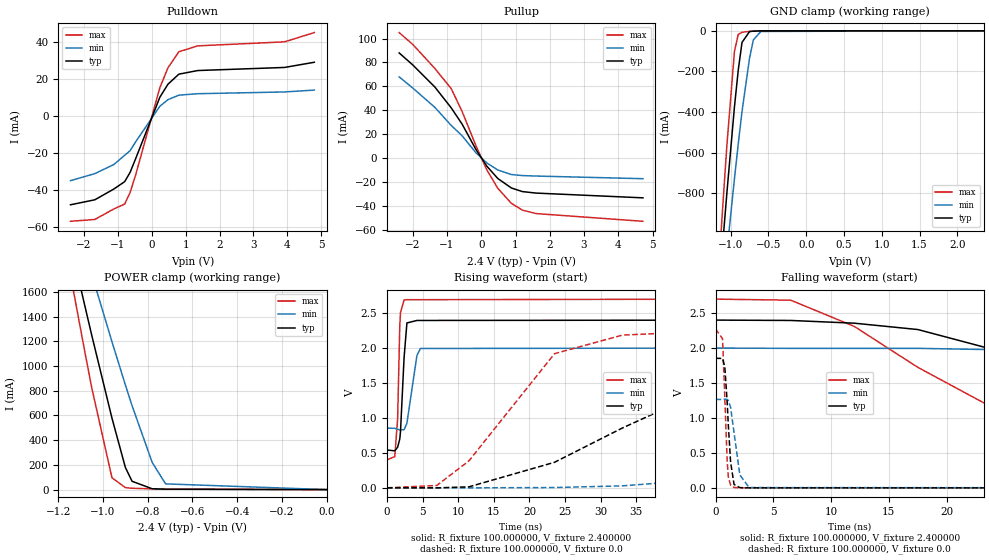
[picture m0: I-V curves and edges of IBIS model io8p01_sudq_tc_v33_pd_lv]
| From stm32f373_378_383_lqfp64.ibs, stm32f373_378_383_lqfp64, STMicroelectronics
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|   Model io8p01_sudq_tc_v33_pd_lv
[Model]  io8p01_sudq_tc_v33_pd_lv
Model_type I/O
Polarity   Non-Inverting
Enable   Active-Low
Vinl =   0.720000V
Vinh =   1.680000V
Vmeas =  1.200000V
Cref =   50.000000pF
Rref =   100.000000M
Vref =   0.0V
C_comp   1.373400pF   1.288200pF   1.481900pF
[Temperature Range]   25.000000   0.125000k   -40.000000
[Pullup Reference]   2.400000V   2.000000V   2.700000V
[Pulldown Reference]   0.0V   0.0V   0.0V
[POWER Clamp Reference]   2.400000V   2.000000V   2.700000V
[GND Clamp Reference]   0.0V   0.0V   0.0V
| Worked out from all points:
|   slope of the pulldown table from 0 to 0.36 V, typ, clamps not added: 25.7 ohm
|   slope of the pullup table from 0 to 0.36 V, typ, clamps not added: 26.8 ohm
|   GND clamp passes 1 mA (typ) near -0.67 V on its own axis
|   POWER clamp passes 1 mA (typ) near -0.60 V on its own axis
|   rising waveform, R_fixture 100.000000, V_fixture 2.400000: 20-80 % time 483ps typ, 801ps min, 337ps max; typ from 0.541 V to 2.4 V
|   rising waveform, R_fixture 100.000000, V_fixture 0.0: 20-80 % time 22.2ns typ, 64.5ns min, 10.4ns max; typ from 0 V to 1.85 V
|   falling waveform, R_fixture 100.000000, V_fixture 2.400000: 20-80 % time 28.7ns typ, 67.7ns min, 14.6ns max; typ from 2.4 V to 0.541 V
|   falling waveform, R_fixture 100.000000, V_fixture 0.0: 20-80 % time 389ps typ, 566ps min, 289ps max; typ from 1.85 V to 0 V
[Pulldown]
|Voltage   I(typ)   I(min)   I(max)
-2.4V     -47.8mA    -34.8mA    -56.7mA
-1.68V    -45.1mA    -31mA      -55.7mA
-1.12V    -39.3mA    -26.1mA    -50.03mA
-800mV    -35.33mA   -21.13mA   -47.42mA
-640mV    -30.33mA   -18.65mA   -41.16mA
-480mV    -23.12mA   -14mA      -31.94mA
240mV     10.22mA    5.339mA    15.38mA
480mV     17.22mA    8.864mA    26.1mA
800mV     22.59mA    11.27mA    34.68mA
1.36V     24.54mA    12.05mA    37.84mA
3.92V     26.2mA     13mA       40mA
4.8V      29mA       14mA       45mA
[Pullup]
|Voltage   I(typ)   I(min)   I(max)
-2.4V     88mA       68mA       105mA
-2V       77.9mA     58.6mA     95mA
-1.36V    59.6mA     42.6mA     75.1mA
-880mV    42.13mA    27.44mA    58.22mA
-560mV    28.45mA    18.75mA    39mA
-160mV    7.44mA     4.66mA     10.64mA
160mV     -6.607mA   -3.947mA   -9.704mA
480mV     -16.91mA   -9.806mA   -25.1mA
880mV     -24.89mA   -13.63mA   -37.75mA
1.2V      -27.87mA   -14.5mA    -43.37mA
1.6V      -29.13mA   -14.89mA   -46.24mA
4.72V     -33.1mA    -17.1mA    -52.7mA
[GND_clamp]
|Voltage   I(typ)   I(min)   I(max)
-2.4V     -7.358A    -6.372A    -8.78A
-1.2V     -1.489A    -1.65A     -1.416A
-1.15V    -1.254A    -1.461A    -1.124A
-1.1V     -1.024A    -1.273A    -838.2mA
-1.05V    -797.6mA   -1.088A    -563.2mA
-950mV    -374.6mA   -728.7mA   -100.8mA
-900mV    -194.3mA   -558mA     -18.03mA
-850mV    -56.96mA   -397.5mA   -7.097mA
-750mV    -3.597mA   -133.8mA   -2.788mA
-700mV    -1.53mA    -44.71mA   -1.533mA
-600mV    -249.2uA   -2.951mA   -225.1uA
2.35V     60.02uA    46.69uA    67.1uA
[POWER_clamp]
|Voltage   I(typ)   I(min)   I(max)
-2.4V     9.979A     9.967A     9.901A
-1.17V    2.182A     2.481A     1.978A
-1.14V    1.945A     2.294A     1.683A
-1.11V    1.71A      2.108A     1.391A
-1.08V    1.476A     1.923A     1.102A
-1.05V    1.245A     1.739A     819.9mA
-960mV    578.2mA    1.196A     96.06mA
-900mV    179.5mA    846.7mA    16.04mA
-870mV    67.18mA    678.8mA    10.82mA
-780mV    6.749mA    219.9mA    5.853mA
-720mV    3.355mA    46.34mA    3.808mA
0V        0A         0A         0A
[Ramp]
| variable   typ   min   max
dV/dt_r  1.11240/22.22506n   0.75582/64.51161n   1.36500/10.38664n
dV/dt_f  1.11463/28.69284n   0.68640/67.67893n   1.37925/14.58614n
R_load = 100.000000
[Rising Waveform]
R_fixture= 100.000000
V_fixture= 2.400000
V_fixture_min= 2.000000
V_fixture_max= 2.700000
|time   V(typ)   V(min)   V(max)
0s        541.2mV    853.5mV    400.3mV
1.101ns   528.9mV    851.4mV    446.9mV
1.502ns   582.1mV    836.6mV    993.8mV
1.802ns   698.5mV    829.4mV    2.317V
1.902ns   804.4mV    828.4mV    2.507V
2.402ns   1.859V     831.2mV    2.686V
2.803ns   2.358V     924mV      2.691V
4.204ns   2.394V     1.891V     2.691V
4.705ns   2.394V     1.993V     2.691V
49.85ns   2.399V     1.999V     2.699V
[Rising Waveform]
R_fixture= 100.000000
V_fixture= 0.0
V_fixture_min= 0.0
V_fixture_max= 0.0
|time   V(typ)   V(min)   V(max)
0s        765pV      13.32nV    588.1pV
7.007ns   -399.7uV   -242.6uV   34.41mV
11.51ns   14.32mV    -206.4uV   386.1mV
23.52ns   365.4mV    4.001mV    1.919V
33.03ns   855mV      28.16mV    2.184V
48.05ns   1.553V     143mV      2.254V
66.57ns   1.78V      347.4mV    2.273V
94.09ns   1.838V     715mV      2.275V
139.1ns   1.855V     1.127V     2.275V
249.2ns   1.854V     1.264V     2.275V
[Falling Waveform]
R_fixture= 100.000000
V_fixture= 2.400000
V_fixture_min= 2.000000
V_fixture_max= 2.700000
|time   V(typ)   V(min)   V(max)
0s        2.399V     1.999V     2.699V
6.507ns   2.394V     1.995V     2.684V
12.01ns   2.355V     1.995V     2.309V
17.52ns   2.264V     1.995V     1.723V
27.03ns   1.847V     1.968V     877.4mV
36.04ns   1.471V     1.91V      533.9mV
54.05ns   851.8mV    1.686V     436.9mV
70.57ns   644.3mV    1.492V     409.5mV
125.1ns   547.6mV    1.019V     400mV
249.2ns   541.2mV    853.5mV    400.3mV
[Falling Waveform]
R_fixture= 100.000000
V_fixture= 0.0
V_fixture_min= 0.0
V_fixture_max= 0.0
|time   V(typ)   V(min)   V(max)
0s        1.854V     1.264V     2.275V
600.6ps   1.85V      1.265V     2.132V
800.8ps   1.73V      1.269V     1.288V
1.001ns   1.233V     1.264V     397.9mV
1.101ns   906.2mV    1.25V      159.7mV
1.301ns   367.3mV    1.152V     38.08mV
1.602ns   48.98mV    787mV      5.412mV
2.102ns   3.225mV    184.6mV    350.7uV
2.903ns   181.1uV    4.133mV    301.9uV
49.85ns   765pV      13.32nV    588.1pV
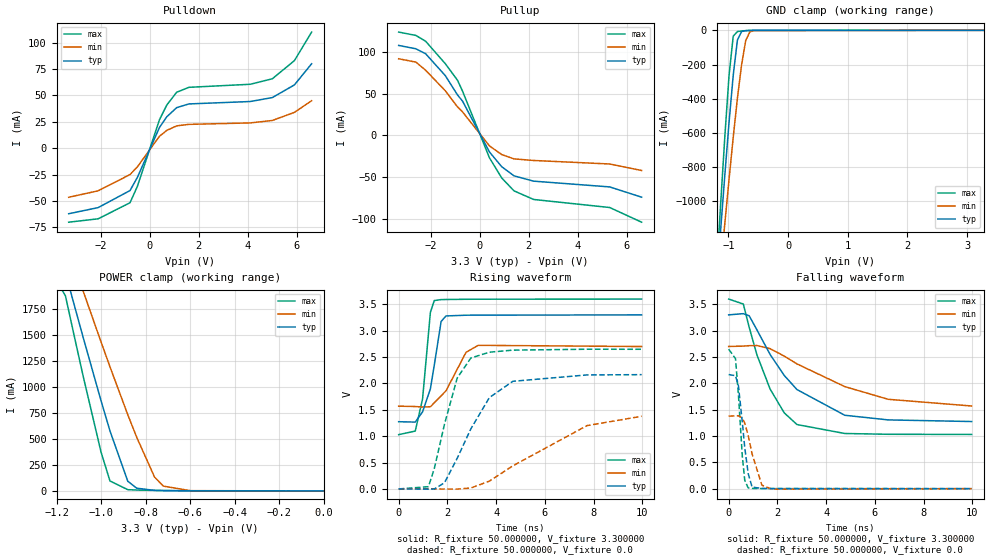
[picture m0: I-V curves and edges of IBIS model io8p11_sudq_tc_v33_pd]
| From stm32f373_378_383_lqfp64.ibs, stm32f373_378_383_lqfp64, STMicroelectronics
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|   Model io8p11_sudq_tc_v33_pd
[Model]  io8p11_sudq_tc_v33_pd
Model_type I/O
Polarity   Non-Inverting
Enable   Active-Low
Vinl =   0.990000V
Vinh =   2.310000V
Vmeas =  1.650000V
Cref =   30.000000pF
Rref =   100.000000M
Vref =   0.0V
C_comp   1.325200pF   1.251200pF   1.426700pF
[Temperature Range]   25.000000   0.125000k   -40.000000
[Pullup Reference]   3.300000V   2.700000V   3.600000V
[Pulldown Reference]   0.0V   0.0V   0.0V
[POWER Clamp Reference]   3.300000V   2.700000V   3.600000V
[GND Clamp Reference]   0.0V   0.0V   0.0V
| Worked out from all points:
|   slope of the pulldown table from 0 to 0.495 V, typ, clamps not added: 21.3 ohm
|   slope of the pullup table from 0 to 0.495 V, typ, clamps not added: 20.9 ohm
|   GND clamp passes 1 mA (typ) near -0.66 V on its own axis
|   POWER clamp passes 1 mA (typ) near -0.60 V on its own axis
|   rising waveform, R_fixture 50.000000, V_fixture 3.300000: 20-80 % time 439ps typ, 839ps min, 340ps max; typ from 1.27 V to 3.3 V
|   rising waveform, R_fixture 50.000000, V_fixture 0.0: 20-80 % time 1.49ns typ, 3.04ns min, 883ps max; typ from 0 V to 2.17 V
|   falling waveform, R_fixture 50.000000, V_fixture 3.300000: 20-80 % time 2.09ns typ, 3.37ns min, 1.32ns max; typ from 3.3 V to 1.27 V
|   falling waveform, R_fixture 50.000000, V_fixture 0.0: 20-80 % time 300ps typ, 423ps min, 224ps max; typ from 2.17 V to 0 V
[Pulldown]
|Voltage   I(typ)   I(min)   I(max)
-3.3V     -62mA      -46.4mA    -70mA
-2.1V     -56.2mA    -40.3mA    -66.8mA
-800mV    -40.04mA   -24.9mA    -51.58mA
-500mV    -27.57mA   -17.6mA    -36.07mA
400mV     19.71mA    11.36mA    27.01mA
700mV     29.83mA    16.93mA    40.97mA
1.1V      38.46mA    21.2mA     53.02mA
1.6V      41.98mA    22.62mA    57.7mA
4.1V      44.26mA    24mA       60.59mA
5V        48mA       26.3mA     65.8mA
5.9V      60mA       34mA       83mA
6.6V      80mA       45mA       110mA
[Pullup]
|Voltage   I(typ)   I(min)   I(max)
-3.3V     108mA      92mA       124mA
-2.6V     104mA      88mA       120mA
-2.2V     98mA       78.2mA     113mA
-1.4V     71.8mA     53.6mA     86.1mA
-900mV    48.51mA    34.23mA    66.14mA
-700mV    41.33mA    28.36mA    53.31mA
400mV     -19.77mA   -12.52mA   -26.8mA
900mV     -37.48mA   -22.89mA   -50.99mA
1.4V      -48.39mA   -28.06mA   -66.43mA
2.2V      -54.79mA   -29.98mA   -76.75mA
5.3V      -61.7mA    -34.2mA    -86.4mA
6.6V      -74mA      -42mA      -104mA
[GND_clamp]
|Voltage   I(typ)   I(min)   I(max)
-3.3V     -9.739A    -9.975A    -9.587A
-1.2V     -1.489A    -1.65A     -1.416A
-1.13V    -1.162A    -1.385A    -1.009A
-1.06V    -842.3mA   -1.125A    -616.9mA
-990mV    -537.1mA   -870.2mA   -263mA
-920mV    -262.5mA   -625.3mA   -33.98mA
-850mV    -56.96mA   -397.5mA   -7.097mA
-780mV    -7.026mA   -202.3mA   -3.727mA
-710mV    -1.792mA   -58.24mA   -1.753mA
-640mV    -564.1uA   -8.795mA   -558.4uA
-570mV    -123.3uA   -1.303mA   -102.2uA
3.28V     84.11uA    64.12uA    93.81uA
[POWER_clamp]
|Voltage   I(typ)   I(min)   I(max)
-3.28V    9.897A     9.838A     9.594A
-1.16V    2.103A     2.419A     1.88A
-1.12V    1.788A     2.17A      1.488A
-1.08V    1.476A     1.923A     1.102A
-1V       868.1mA    1.435A     373.1mA
-960mV    578.2mA    1.196A     96.06mA
-880mV    93.24mA    734.1mA    12.01mA
-840mV    26.3mA     517.4mA    8.56mA
-760mV    5.106mA    134mA      5.119mA
-720mV    3.355mA    46.34mA    3.808mA
-600mV    1.005mA    2.564mA    1.072mA
0V        0A         0A         0A
[Ramp]
| variable   typ   min   max
dV/dt_r  1.29948/1.48828n   0.78702/3.04554n   1.58802/0.88123n
dV/dt_f  1.21518/2.09158n   0.66144/3.38208n   1.54224/1.31504n
R_load = 50.000000
[Rising Waveform]
R_fixture= 50.000000
V_fixture= 3.300000
V_fixture_min= 2.700000
V_fixture_max= 3.600000
|time   V(typ)   V(min)   V(max)
0s        1.274V     1.569V     1.029V
680.7ps   1.267V     1.562V     1.097V
981ps     1.462V     1.552V     1.706V
1.301ns   1.896V     1.557V     3.346V
1.461ns   2.346V     1.633V     3.571V
1.742ns   3.174V     1.765V     3.589V
1.942ns   3.279V     1.859V     3.591V
2.763ns   3.293V     2.589V     3.595V
3.263ns   3.294V     2.722V     3.596V
9.97ns    3.299V     2.699V     3.599V
[Rising Waveform]
R_fixture= 50.000000
V_fixture= 0.0
V_fixture_min= 0.0
V_fixture_max= 0.0
|time   V(typ)   V(min)   V(max)
0s        -14.38uV   -16.71uV   -16.86uV
1.221ns   -4.576mV   -179.1uV   42.7mV
1.461ns   -2.145mV   -967.6uV   383mV
1.882ns   117.6mV    -2.713mV   1.23V
2.402ns   580.6mV    -3.426mV   2.102V
2.963ns   1.139V     17.7mV     2.482V
3.724ns   1.732V     148.3mV    2.592V
4.685ns   2.04V      437.4mV    2.631V
7.728ns   2.161V     1.2V       2.648V
9.97ns    2.166V     1.377V     2.647V
[Falling Waveform]
R_fixture= 50.000000
V_fixture= 3.300000
V_fixture_min= 2.700000
V_fixture_max= 3.600000
|time   V(typ)   V(min)   V(max)
0s        3.299V     2.699V     3.599V
600.6ps   3.322V     2.706V     3.505V
840.8ps   3.282V     2.714V     3.065V
1.161ns   3.013V     2.717V     2.538V
1.702ns   2.546V     2.657V     1.889V
2.282ns   2.148V     2.516V     1.438V
2.803ns   1.881V     2.368V     1.217V
4.765ns   1.393V     1.937V     1.047V
6.547ns   1.305V     1.696V     1.032V
9.97ns    1.274V     1.569V     1.029V
[Falling Waveform]
R_fixture= 50.000000
V_fixture= 0.0
V_fixture_min= 0.0
V_fixture_max= 0.0
|time   V(typ)   V(min)   V(max)
0s        2.166V     1.377V     2.647V
280.3ps   2.144V     1.381V     2.468V
400.4ps   1.953V     1.383V     1.783V
560.6ps   1.257V     1.34V      611.5mV
660.7ps   775.3mV    1.24V      154.8mV
800.8ps   286.4mV    1.01V      14.42mV
961ps     30.06mV    660.4mV    4.006mV
1.361ns   3.093mV    66.35mV    1.654mV
1.782ns   1.67mV     -9.925mV   1.142mV
9.97ns    -14.38uV   -16.71uV   -16.86uV
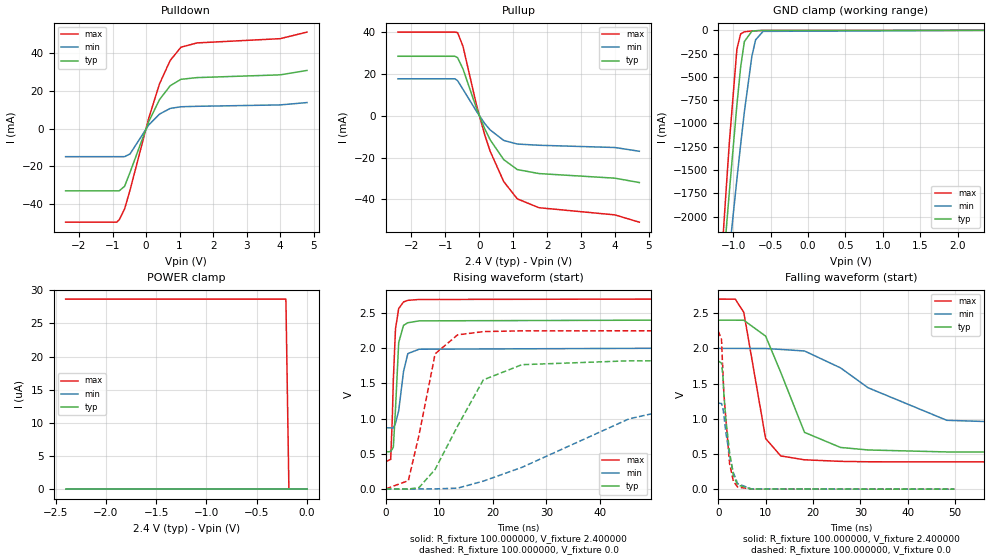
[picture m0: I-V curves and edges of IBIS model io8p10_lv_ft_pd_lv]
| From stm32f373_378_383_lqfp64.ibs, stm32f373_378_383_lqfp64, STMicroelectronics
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|   Model io8p10_lv_ft_pd_lv
[Model]  io8p10_lv_ft_pd_lv
Model_type I/O
Polarity   Non-Inverting
Enable   Active-Low
Vinl =   0.720000V
Vinh =   1.680000V
Vmeas =  1.200000V
Cref =   50.000000pF
Rref =   100.000000M
Vref =   0.0V
C_comp   5.024800pF   4.846300pF   5.260300pF
[Temperature Range]   25.000000   0.125000k   -40.000000
[Pullup Reference]   2.400000V   2.000000V   2.700000V
[Pulldown Reference]   0.0V   0.0V   0.0V
[POWER Clamp Reference]   2.400000V   2.000000V   2.700000V
[GND Clamp Reference]   0.0V   0.0V   0.0V
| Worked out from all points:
|   slope of the pulldown table from 0 to 0.36 V, typ, clamps not added: 25.5 ohm
|   slope of the pullup table from 0 to 0.36 V, typ, clamps not added: 28.4 ohm
|   GND clamp passes 1 mA (typ) near -0.60 V on its own axis
|   rising waveform, R_fixture 100.000000, V_fixture 2.400000: 20-80 % time 717ps typ, 1.18ns min, 635ps max; typ from 0.525 V to 2.4 V
|   rising waveform, R_fixture 100.000000, V_fixture 0.0: 20-80 % time 7.16ns typ, 21ns min, 3.56ns max; typ from 0 V to 1.82 V
|   falling waveform, R_fixture 100.000000, V_fixture 2.400000: 20-80 % time 6.43ns typ, 17.4ns min, 3.43ns max; typ from 2.4 V to 0.525 V
|   falling waveform, R_fixture 100.000000, V_fixture 0.0: 20-80 % time 1.62ns typ, 1.84ns min, 1.35ns max; typ from 1.82 V to 0 V
[Pulldown]
|Voltage   I(typ)   I(min)   I(max)
-2.4V     -33.16mA   -14.98mA   -49.86mA
-880mV    -33.16mA   -14.98mA   -49.86mA
-800mV    -33.16mA   -14.98mA   -48.55mA
-640mV    -30.75mA   -14.98mA   -42.77mA
-480mV    -23.43mA   -13.57mA   -32.92mA
80mV      3.651mA    1.905mA    5.506mA
400mV     15.37mA    7.665mA    23.73mA
720mV     22.75mA    10.69mA    36.23mA
1.04V     26.18mA    11.57mA    43.27mA
1.52V     27.09mA    11.81mA    45.55mA
4V        28.55mA    12.55mA    47.81mA
4.8V      30.9mA     13.81mA    51.31mA
[Pullup]
|Voltage   I(typ)   I(min)   I(max)
-2.4V     28.54mA    17.74mA    40.13mA
-720mV    28.54mA    17.74mA    40.13mA
-640mV    27.85mA    16.83mA    39.87mA
-480mV    22.4mA     12.66mA    33.23mA
-80mV     3.427mA    2.067mA    4.957mA
160mV     -6.219mA   -3.714mA   -9.136mA
320mV     -11.51mA   -6.781mA   -16.98mA
720mV     -21mA      -11.8mA    -31.53mA
1.12V     -25.77mA   -13.54mA   -39.82mA
1.76V     -27.69mA   -14.12mA   -44.06mA
4V        -29.9mA    -15.2mA    -47.5mA
4.72V     -32mA      -17mA      -51mA
[GND_clamp]
|Voltage   I(typ)   I(min)   I(max)
-2.4V     -9.914A    -9.862A    -9.419A
-1.2V     -3.21A     -3.567A    -3.02A
-1.15V    -2.709A    -3.165A    -2.399A
-1.1V     -2.213A    -2.766A    -1.788A
-1.05V    -1.726A    -2.371A    -1.195A
-950mV    -800.5mA   -1.599A    -202.1mA
-900mV    -395mA     -1.228A    -38.18mA
-850mV    -120.2mA   -874.5mA   -15.93mA
-750mV    -9.822mA   -279.4mA   -7.289mA
-700mV    -4.75mA    -102mA     -4.527mA
-600mV    -1.046mA   -11.1mA    -938uA
2.35V     59.64uA    46.24uA    66.77uA
[POWER_clamp]
|Voltage   I(typ)   I(min)   I(max)
-2.4V     0A         0A         28.66uA
-210mV    0A         0A         28.66uA
-180mV    0A         0A         0A
0V        0A         0A         0A
[Ramp]
| variable   typ   min   max
dV/dt_r  1.09212/7.14948n   0.73194/20.95797n   1.34886/3.55687n
dV/dt_f  1.12429/6.42351n   0.67631/17.34783n   1.38700/3.42959n
R_load = 100.000000
[Rising Waveform]
R_fixture= 100.000000
V_fixture= 2.400000
V_fixture_min= 2.000000
V_fixture_max= 2.700000
|time   V(typ)   V(min)   V(max)
0s        524.8mV    868.7mV    387.2mV
900.9ps   531mV      867.7mV    419.2mV
1.201ns   566.6mV    866.4mV    995.7mV
1.401ns   594.9mV    865.8mV    1.556V
1.802ns   1.137V     933.7mV    2.276V
2.402ns   2.082V     1.113V     2.565V
3.303ns   2.325V     1.669V     2.658V
4.104ns   2.362V     1.923V     2.681V
6.206ns   2.389V     1.986V     2.693V
49.85ns   2.399V     1.999V     2.699V
[Rising Waveform]
R_fixture= 100.000000
V_fixture= 0.0
V_fixture_min= 0.0
V_fixture_max= 0.0
|time   V(typ)   V(min)   V(max)
0s        4.868nV    72.49nV    3.74nV
4.204ns   -2.388mV   -3.999mV   117.2mV
6.206ns   18.86mV    -722.9uV   767.1mV
9.209ns   277.1mV    -111uV     1.92V
13.41ns   892.5mV    10.44mV    2.19V
18.22ns   1.55V      110.3mV    2.236V
25.43ns   1.766V     305.9mV    2.247V
45.45ns   1.821V     995.7mV    2.248V
51.65ns   1.821V     1.101V     2.248V
99.7ns    1.82V      1.221V     2.248V
[Falling Waveform]
R_fixture= 100.000000
V_fixture= 2.400000
V_fixture_min= 2.000000
V_fixture_max= 2.700000
|time   V(typ)   V(min)   V(max)
0s        2.399V     1.999V     2.699V
3.604ns   2.399V     1.998V     2.698V
5.405ns   2.398V     1.998V     2.51V
10.01ns   2.173V     1.997V     719.1mV
13.21ns   1.657V     1.984V     471.6mV
18.22ns   806.3mV    1.962V     416.9mV
25.83ns   592.2mV    1.722V     394.8mV
31.63ns   556.6mV    1.44V      388.8mV
48.25ns   528.5mV    977.6mV    387.1mV
99.7ns    524.8mV    868.7mV    387.2mV
[Falling Waveform]
R_fixture= 100.000000
V_fixture= 0.0
V_fixture_min= 0.0
V_fixture_max= 0.0
|time   V(typ)   V(min)   V(max)
0s        1.82V      1.221V     2.248V
700.7ps   1.79V      1.216V     2.125V
1.001ns   1.603V     1.151V     1.644V
1.201ns   1.349V     1.052V     1.359V
1.602ns   997.1mV    808mV      1.009V
2.402ns   527.1mV    480.5mV    363.9mV
3.203ns   195.2mV    232.4mV    113mV
4.104ns   59.58mV    79.46mV    30.06mV
7.007ns   2.679mV    2.857mV    1.682mV
49.85ns   4.868nV    72.49nV    3.74nV
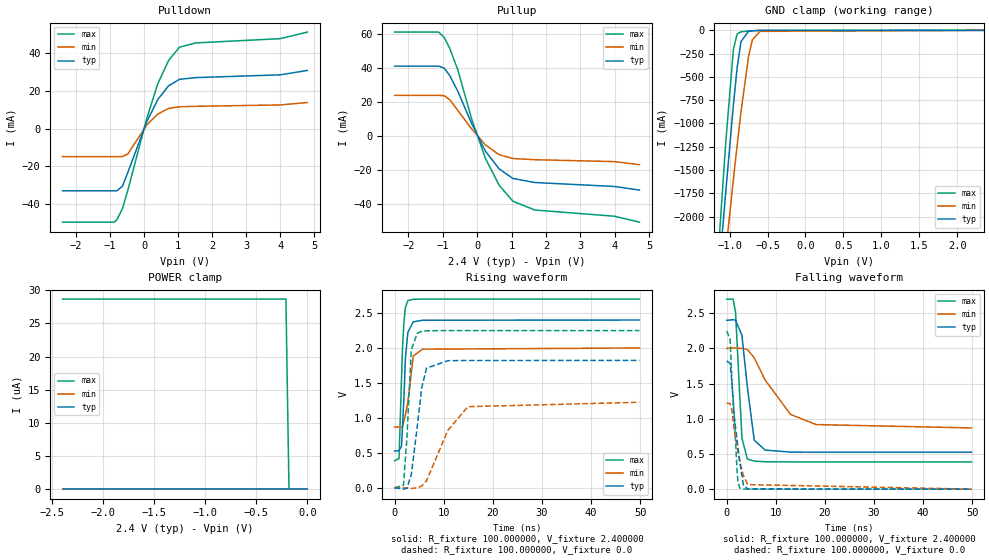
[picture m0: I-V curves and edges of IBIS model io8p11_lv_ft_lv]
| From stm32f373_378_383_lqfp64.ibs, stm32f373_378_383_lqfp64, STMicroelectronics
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|   Model io8p11_lv_ft_lv
[Model]  io8p11_lv_ft_lv
Model_type I/O
Polarity   Non-Inverting
Enable   Active-Low
Vinl =   0.720000V
Vinh =   1.680000V
Vmeas =  1.200000V
Cref =   50.000000pF
Rref =   100.000000M
Vref =   0.0V
C_comp   5.024800pF   4.846300pF   5.260300pF
[Temperature Range]   25.000000   0.125000k   -40.000000
[Pullup Reference]   2.400000V   2.000000V   2.700000V
[Pulldown Reference]   0.0V   0.0V   0.0V
[POWER Clamp Reference]   2.400000V   2.000000V   2.700000V
[GND Clamp Reference]   0.0V   0.0V   0.0V
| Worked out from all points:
|   slope of the pulldown table from 0 to 0.36 V, typ, clamps not added: 25.5 ohm
|   slope of the pullup table from 0 to 0.36 V, typ, clamps not added: 28.4 ohm
|   GND clamp passes 1 mA (typ) near -0.60 V on its own axis
|   rising waveform, R_fixture 100.000000, V_fixture 2.400000: 20-80 % time 723ps typ, 1.17ns min, 636ps max; typ from 0.525 V to 2.4 V
|   rising waveform, R_fixture 100.000000, V_fixture 0.0: 20-80 % time 1.8ns typ, 4.71ns min, 954ps max; typ from 0 V to 1.82 V
|   falling waveform, R_fixture 100.000000, V_fixture 2.400000: 20-80 % time 1.6ns typ, 6.25ns min, 915ps max; typ from 2.4 V to 0.525 V
|   falling waveform, R_fixture 100.000000, V_fixture 0.0: 20-80 % time 1.59ns typ, 1.86ns min, 1.06ns max; typ from 1.82 V to 0 V
[Pulldown]
|Voltage   I(typ)   I(min)   I(max)
-2.4V     -33.16mA   -14.98mA   -49.86mA
-880mV    -33.16mA   -14.98mA   -49.86mA
-800mV    -33.16mA   -14.98mA   -48.55mA
-640mV    -30.75mA   -14.98mA   -42.77mA
-480mV    -23.43mA   -13.57mA   -32.92mA
80mV      3.651mA    1.905mA    5.506mA
400mV     15.37mA    7.665mA    23.73mA
720mV     22.75mA    10.69mA    36.23mA
1.04V     26.18mA    11.57mA    43.27mA
1.52V     27.09mA    11.81mA    45.55mA
4V        28.55mA    12.55mA    47.81mA
4.8V      30.9mA     13.81mA    51.31mA
[Pullup]
|Voltage   I(typ)   I(min)   I(max)
-2.4V     41.22mA    23.93mA    61.35mA
-1.12V    41.22mA    23.93mA    61.35mA
-960mV    40.07mA    23.79mA    58.26mA
-800mV    35.79mA    21.42mA    51.95mA
-560mV    26.31mA    15.01mA    38.93mA
-160mV    7.327mA    4.151mA    10.02mA
240mV     -8.976mA   -5.327mA   -13.21mA
640mV     -19.5mA    -11.09mA   -29.16mA
1.04V     -25.15mA   -13.38mA   -38.61mA
1.68V     -27.56mA   -14.07mA   -43.81mA
4V        -29.9mA    -15.2mA    -47.5mA
4.72V     -32mA      -17mA      -51mA
[GND_clamp]
|Voltage   I(typ)   I(min)   I(max)
-2.4V     -9.914A    -9.862A    -9.419A
-1.2V     -3.21A     -3.567A    -3.02A
-1.15V    -2.709A    -3.165A    -2.399A
-1.1V     -2.213A    -2.766A    -1.788A
-1.05V    -1.726A    -2.371A    -1.195A
-950mV    -800.5mA   -1.599A    -202.1mA
-900mV    -394.9mA   -1.228A    -38.17mA
-850mV    -120.2mA   -874.5mA   -15.91mA
-750mV    -9.807mA   -279.4mA   -7.273mA
-700mV    -4.736mA   -102mA     -4.51mA
-600mV    -1.032mA   -11.09mA   -922.6uA
2.35V     0A         0A         0A
[POWER_clamp]
|Voltage   I(typ)   I(min)   I(max)
-2.4V     0A         0A         28.66uA
-210mV    0A         0A         28.66uA
-180mV    0A         0A         0A
0V        0A         0A         0A
[Ramp]
| variable   typ   min   max
dV/dt_r  1.09296/1.79468n   0.73362/4.70375n   1.34958/0.94964n
dV/dt_f  1.12489/1.60302n   0.67774/6.24023n   1.38754/0.91175n
R_load = 100.000000
[Rising Waveform]
R_fixture= 100.000000
V_fixture= 2.400000
V_fixture_min= 2.000000
V_fixture_max= 2.700000
|time   V(typ)   V(min)   V(max)
0s        525.2mV    870.3mV    387.4mV
900.9ps   531.1mV    869.4mV    417mV
1.401ns   591.6mV    867.8mV    1.542V
1.602ns   859.8mV    875.4mV    1.987V
1.902ns   1.285V     960.1mV    2.366V
2.202ns   1.859V     1.045V     2.581V
2.703ns   2.223V     1.228V     2.678V
3.804ns   2.374V     1.885V     2.697V
5.706ns   2.397V     1.983V     2.7V
49.85ns   2.4V       2V         2.7V
[Rising Waveform]
R_fixture= 100.000000
V_fixture= 0.0
V_fixture_min= 0.0
V_fixture_max= 0.0
|time   V(typ)   V(min)   V(max)
0s        -26.02uV   -10.95uV   -23.57uV
1.802ns   -20.38mV   -1.088mV   34.38mV
2.503ns   -8.388mV   -4.341mV   708.5mV
3.403ns   189mV      -9.868mV   1.973V
4.605ns   871mV      -1.233mV   2.211V
5.506ns   1.427V     24.11mV    2.236V
6.507ns   1.711V     99.82mV    2.246V
10.81ns   1.818V     817.8mV    2.249V
14.91ns   1.821V     1.16V      2.249V
49.85ns   1.822V     1.223V     2.249V
[Falling Waveform]
R_fixture= 100.000000
V_fixture= 2.400000
V_fixture_min= 2.000000
V_fixture_max= 2.700000
|time   V(typ)   V(min)   V(max)
0s        2.4V       2V         2.7V
1.301ns   2.408V     2.007V     2.702V
1.802ns   2.402V     2.006V     2.52V
3.103ns   2.186V     2.001V     725.7mV
4.204ns   1.456V     1.986V     428.9mV
5.606ns   697.2mV    1.868V     398.5mV
7.808ns   555.4mV    1.553V     389.6mV
13.01ns   526.9mV    1.062V     387.4mV
18.22ns   525.3mV    918mV      387.5mV
49.85ns   525.2mV    870.3mV    387.4mV
[Falling Waveform]
R_fixture= 100.000000
V_fixture= 0.0
V_fixture_min= 0.0
V_fixture_max= 0.0
|time   V(typ)   V(min)   V(max)
0s        1.822V     1.223V     2.249V
700.7ps   1.791V     1.217V     2.129V
1.101ns   1.487V     1.109V     1.483V
1.502ns   1.055V     861.3mV    1.084V
2.102ns   701.9mV    602.4mV    274.9mV
2.302ns   591.8mV    521.9mV    92.81mV
2.703ns   369.2mV    381.4mV    12.51mV
3.403ns   57.01mV    191.5mV    1.707mV
4.304ns   3.921mV    64.86mV    693.9uV
49.85ns   -26.02uV   -10.95uV   -23.57uV
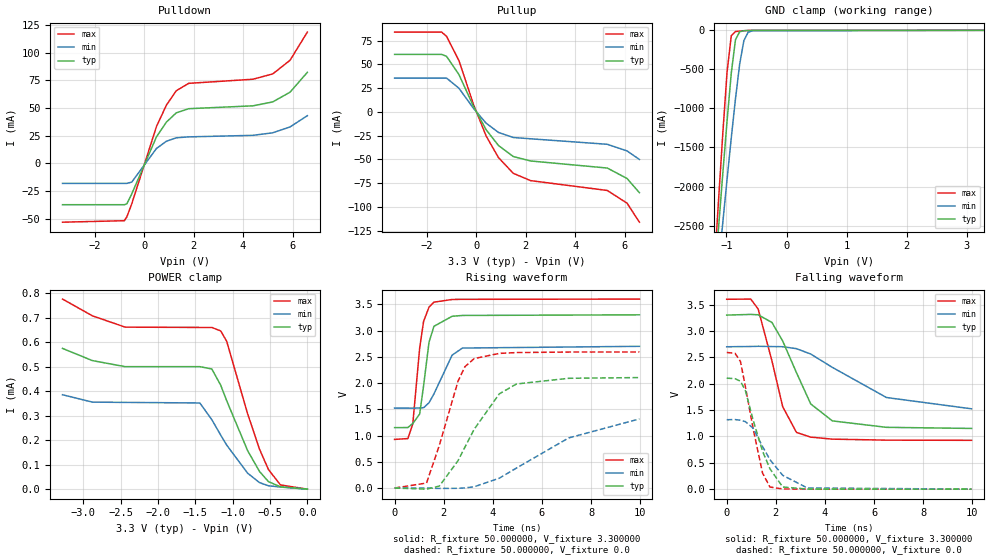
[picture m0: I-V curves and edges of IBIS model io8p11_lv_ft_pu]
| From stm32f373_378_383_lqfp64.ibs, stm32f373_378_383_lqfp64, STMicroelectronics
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|   Model io8p11_lv_ft_pu
[Model]  io8p11_lv_ft_pu
Model_type I/O
Polarity   Non-Inverting
Enable   Active-Low
Vinl =   0.990000V
Vinh =   2.310000V
Vmeas =  1.650000V
Cref =   30.000000pF
Rref =   100.000000M
Vref =   0.0V
C_comp   5.028100pF   4.857200pF   5.254400pF
[Temperature Range]   25.000000   0.125000k   -40.000000
[Pullup Reference]   3.300000V   2.700000V   3.600000V
[Pulldown Reference]   0.0V   0.0V   0.0V
[POWER Clamp Reference]   3.300000V   2.700000V   3.600000V
[GND Clamp Reference]   0.0V   0.0V   0.0V
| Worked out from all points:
|   slope of the pulldown table from 0 to 0.495 V, typ, clamps not added: 20.9 ohm
|   slope of the pullup table from 0 to 0.495 V, typ, clamps not added: 22.2 ohm
|   GND clamp passes 1 mA (typ) near -0.59 V on its own axis
|   rising waveform, R_fixture 50.000000, V_fixture 3.300000: 20-80 % time 376ps typ, 721ps min, 342ps max; typ from 1.15 V to 3.3 V
|   rising waveform, R_fixture 50.000000, V_fixture 0.0: 20-80 % time 1.6ns typ, 3.09ns min, 980ps max; typ from 0.001 V to 2.1 V
|   falling waveform, R_fixture 50.000000, V_fixture 3.300000: 20-80 % time 1.26ns typ, 2.63ns min, 827ps max; typ from 3.3 V to 1.15 V
|   falling waveform, R_fixture 50.000000, V_fixture 0.0: 20-80 % time 851ps typ, 1.08ns min, 650ps max; typ from 2.1 V to 0.001 V
[Pulldown]
|Voltage   I(typ)   I(min)   I(max)
-3.3V     -37.45mA   -18.2mA    -53.24mA
-800mV    -37.45mA   -18.2mA    -51.9mA
-700mV    -36.7mA    -18.2mA    -48.48mA
-500mV    -27.71mA   -17.01mA   -36.66mA
500mV     23.91mA    13.38mA    33.24mA
900mV     37.17mA    19.88mA    52.48mA
1.3V      45.55mA    23.01mA    65.5mA
1.8V      49.29mA    23.83mA    72.18mA
4.4V      51.88mA    25.21mA    75.91mA
5.2V      55.41mA    27.53mA    80.72mA
5.9V      64.2mA     32.82mA    93.01mA
6.6V      82.13mA    42.97mA    118.5mA
[Pullup]
|Voltage   I(typ)   I(min)   I(max)
-3.3V     60.63mA    35.66mA    84.09mA
-1.4V     60.63mA    35.66mA    84.09mA
-1.2V     58.55mA    35.66mA    79.71mA
-700mV    39.46mA    25.05mA    54.09mA
-100mV    5.36mA     3.465mA    7.201mA
400mV     -18.61mA   -11.78mA   -25.23mA
900mV     -35.28mA   -21.54mA   -48mA
1.5V      -46.91mA   -26.86mA   -64.57mA
2.2V      -51.57mA   -28.22mA   -72.25mA
5.3V      -59mA      -34mA      -82.6mA
6.1V      -70mA      -41mA      -96mA
6.6V      -85mA      -50mA      -116mA
[GND_clamp]
|Voltage   I(typ)   I(min)   I(max)
-3.3V     -9.706A    -9.438A    -9.292A
-1.2V     -3.211A    -3.571A    -3.02A
-1.13V    -2.511A    -3.008A    -2.153A
-1.06V    -1.824A    -2.453A    -1.311A
-990mV    -1.16A     -1.907A    -534mA
-920mV    -548mA     -1.377A    -70.08mA
-850mV    -120.4mA   -875.9mA   -15.9mA
-780mV    -17.66mA   -430.9mA   -9.191mA
-710mV    -5.44mA    -130.8mA   -5.02mA
-640mV    -2.077mA   -25.65mA   -2.003mA
-570mV    -540.4uA   -6.293mA   -433.9uA
3.28V     0A         0A         0A
[POWER_clamp]
|Voltage   I(typ)   I(min)   I(max)
-3.28V    574uA      385.1uA    775.2uA
-2.88V    524.3uA    354.9uA    706.9uA
-2.44V    499.5uA    353.8uA    660.7uA
-1.44V    499.5uA    351.5uA    659.5uA
-1.28V    490.2uA    283.5uA    659.5uA
-1.16V    423.6uA    220uA      645.1uA
-1.08V    360.3uA    179.6uA    602.6uA
-800mV    157uA      65.19uA    307.1uA
-640mV    71.83uA    26.56uA    162.4uA
-520mV    30.52uA    13.8uA     79.51uA
-360mV    9.626uA    8.662uA    17.31uA
0V        0A         0A         0A
[Ramp]
| variable   typ   min   max
dV/dt_r  1.26162/1.59499n   0.73510/3.06541n   1.55427/0.97896n
dV/dt_f  1.28748/1.26131n   0.68538/2.62177n   1.60393/0.82609n
R_load = 50.000000
[Rising Waveform]
R_fixture= 50.000000
V_fixture= 3.300000
V_fixture_min= 2.700000
V_fixture_max= 3.600000
|time   V(typ)   V(min)   V(max)
0s        1.152V     1.524V     926.8mV
540.5ps   1.153V     1.523V     943.3mV
740.7ps   1.23V      1.522V     1.223V
1.021ns   1.411V     1.526V     2.669V
1.181ns   1.951V     1.531V     3.175V
1.401ns   2.778V     1.625V     3.446V
1.602ns   3.081V     1.794V     3.541V
2.342ns   3.272V     2.532V     3.592V
2.763ns   3.288V     2.667V     3.595V
9.97ns    3.3V       2.7V       3.6V
[Rising Waveform]
R_fixture= 50.000000
V_fixture= 0.0
V_fixture_min= 0.0
V_fixture_max= 0.0
|time   V(typ)   V(min)   V(max)
0s        1.088mV    1.205mV    1.044mV
1.301ns   -20.54mV   -46.85uV   96.31mV
1.822ns   38.57mV    -6.667mV   814.7mV
2.583ns   521.4mV    -3.919mV   2.036V
2.863ns   778.9mV    2.798mV    2.312V
3.243ns   1.122V     25.31mV    2.467V
4.264ns   1.795V     188.3mV    2.565V
4.965ns   1.983V     382.3mV    2.581V
7.087ns   2.091V     954.8mV    2.591V
9.97ns    2.105V     1.317V     2.592V
[Falling Waveform]
R_fixture= 50.000000
V_fixture= 3.300000
V_fixture_min= 2.700000
V_fixture_max= 3.600000
|time   V(typ)   V(min)   V(max)
0s        3.3V       2.7V       3.6V
981ps     3.313V     2.705V     3.604V
1.281ns   3.306V     2.709V     3.417V
1.842ns   3.161V     2.704V     2.434V
2.282ns   2.808V     2.701V     1.563V
2.843ns   2.208V     2.664V     1.076V
3.423ns   1.616V     2.562V     987.4mV
4.304ns   1.295V     2.309V     949.2mV
6.507ns   1.173V     1.738V     930mV
9.97ns    1.152V     1.524V     926.8mV
[Falling Waveform]
R_fixture= 50.000000
V_fixture= 0.0
V_fixture_min= 0.0
V_fixture_max= 0.0
|time   V(typ)   V(min)   V(max)
0s        2.105V     1.317V     2.592V
340.3ps   2.095V     1.32V      2.576V
560.6ps   2.047V     1.308V     2.422V
760.8ps   1.872V     1.281V     1.947V
1.081ns   1.303V     1.154V     1.138V
1.461ns   720.4mV    809.3mV    305.2mV
1.762ns   387mV      560.3mV    41.2mV
2.282ns   41.99mV    263.1mV    5.086mV
3.283ns   3.206mV    24.5mV     1.965mV
9.97ns    1.088mV    1.205mV    1.044mV
